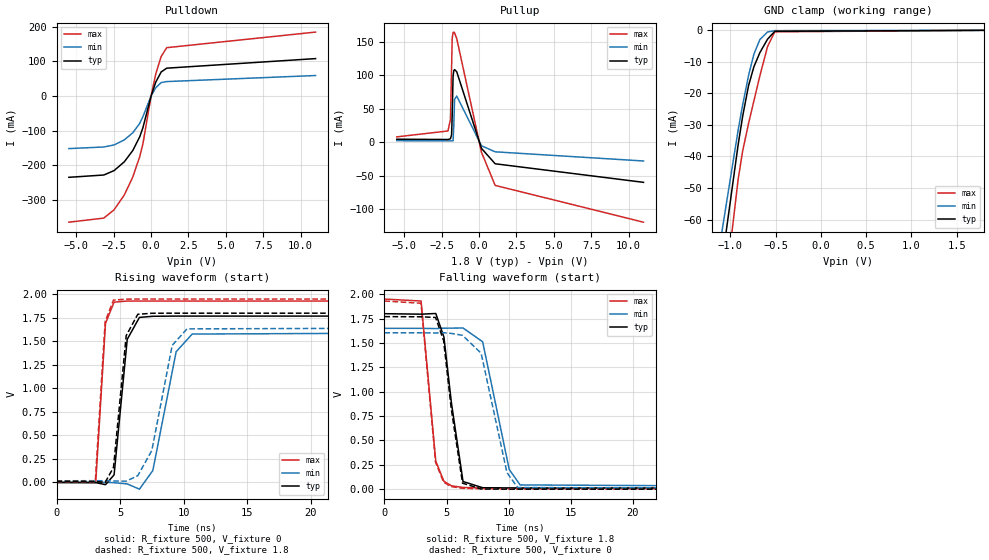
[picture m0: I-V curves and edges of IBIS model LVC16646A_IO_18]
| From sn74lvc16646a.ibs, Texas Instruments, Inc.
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[Model]   LVC16646A_IO_18
Model_type  I/O
Vinl=0.5775
Vinh=1.2675
Enable   Active-Low
Vref =   0
Rref =   1000
Cref =   30p
Vmeas =   0.9
| variable   typ   min   max
C_comp   8.38pF   7.45pF   9.23pF
| C_pullup   11.64pF   7.97pF   13.67pF
| C_pulldown   18.07pF   9.92pF   27.45pF
| C_tri-state   8.38pF   7.45pF   9.23pF
[Temperature Range]   40   100   -40
| Ambient temperature   25   85   -40
[Voltage range]   1.8   1.65   1.95
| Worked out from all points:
|   slope of the pulldown table from 0 to 0.27 V, typ, clamps not added: 7.6 ohm
|   slope of the pullup table from 0 to 0.27 V, typ, clamps not added: 18.9 ohm
|   GND clamp passes 1 mA (typ) near -0.54 V on its own axis
|   rising waveform, R_fixture 500, V_fixture 0: 20-80 % time 680ps typ, 1.28ns min, 406ps max; typ from 0 V to 1.77 V
|   falling waveform, R_fixture 500, V_fixture 1.8: 20-80 % time 837ps typ, 1.48ns min, 659ps max; typ from 1.8 V to 0.012 V
|   rising waveform, R_fixture 500, V_fixture 1.8: 20-80 % time 684ps typ, 1.34ns min, 405ps max; typ from 0.012 V to 1.8 V
|   falling waveform, R_fixture 500, V_fixture 0: 20-80 % time 828ps typ, 1.55ns min, 649ps max; typ from 1.77 V to 0 V
[GND Clamp]
| LVC16646A_IO_18
|   Voltage   I(typ)   I(min)   I(max)
-5.5V     -1.242A    -1.069A    -1.5A
-1.225V   -103.5mA   -89.45mA   -127.4mA
-1.15V    -86.25mA   -74.65mA   -106.5mA
-1.085V   -71.67mA   -62.15mA   -88.91mA
-915mV    -36.28mA   -31.65mA   -47.24mA
-865mV    -27.25mA   -23.61mA   -38.27mA
-800mV    -17.54mA   -14.3mA    -29.54mA
-740mV    -11.49mA   -7.496mA   -22.29mA
-675mV    -7.095mA   -2.938mA   -14.46mA
-590mV    -2.803mA   -517.9uA   -5.15mA
-510mV    -314.3uA   -105.1uA   -473.6uA
1.8V      74.45pA    10.28nA    30.94pA
[Pulldown]
| LVC16646A_IO_18
|   Voltage   I(typ)   I(min)   I(max)
-5.5V     -234.2mA   -151.4mA   -363.5mA
-3.16V    -227.5mA   -146.8mA   -351.7mA
-2.475V   -214.8mA   -140.9mA   -327.7mA
-1.795V   -189.6mA   -126.4mA   -285.3mA
-1.23V    -157.3mA   -106.1mA   -233.9mA
-760mV    -117.4mA   -78.76mA   -174.5mA
-545mV    -90.84mA   -58.98mA   -137mA
5mV       753.9uA    468.2uA    1.172mA
310mV     39.91mA    23.88mA    63.34mA
675mV     69.47mA    38.9mA     114.1mA
1.045V    80.31mA    41.7mA     139.4mA
11V       107.9mA    59.16mA    184.3mA
[Pullup]
| LVC16646A_IO_18
|   Voltage   I(typ)   I(min)   I(max)
-5.5V     4.549mA    2.354mA    8.057mA
-2.075V   4.074mA    2.072mA    16.88mA
-1.91V    5.207mA    2.05mA     34.32mA
-1.835V   11.22mA    2.037mA    111.3mA
-1.795V   39.25mA    2.03mA     155.2mA
-1.735V   98.9mA     2.253mA    164mA
-1.685V   107.2mA    27.08mA    164.7mA
-1.635V   108.7mA    64.12mA    163.5mA
-1.49V    105.3mA    69.03mA    155mA
165mV     -9.185mA   -5.242mA   -15.07mA
1.08V     -32.17mA   -14.31mA   -64.48mA
11V       -59.92mA   -28mA      -119.5mA
[Ramp]
| LVC16646A_IO_18
| variable   typ   min   max
dV/dt_r   1.10/7.07E-10   1.01/1.35E-09   1.17/4.16E-10
dV/dt_f   1.08/8.41E-10   0.98/1.48E-09   1.17/6.65E-10
R_load = 500
[Rising Waveform]
| LVC16646A_IO_18
R_fixture =   500
C_fixture =   0
L_fixture =   0
V_fixture =   0
V_fixture_min = 0
V_fixture_max = 0
|   Time   V(typ)   V(min)   V(max)
0s        342.7pV    2.139nV    223.3pV
3.085ns   -1.758mV   990.8uV    -792.7uV
3.855ns   -23.78mV   853.3uV    1.691V
4.53ns    80.73mV    -2.648mV   1.917V
5.565ns   1.522V     -15.41mV   1.929V
6.525ns   1.755V     -71.45mV   1.929V
7.58ns    1.767V     126.6mV    1.929V
9.415ns   1.769V     1.39V      1.929V
10.68ns   1.769V     1.578V     1.929V
50ns      1.769V     1.601V     1.929V
[Falling Waveform]
| LVC16646A_IO_18
R_fixture =   500
C_fixture =   0
L_fixture =   0
V_fixture =   1.8
V_fixture_min = 1.65
V_fixture_max = 1.95
|   Time   V(typ)   V(min)   V(max)
0s        1.8V       1.65V      1.95V
2.95ns    1.795V     1.65V      1.93V
4.135ns   1.802V     1.647V     288.3mV
4.79ns    1.561V     1.651V     80.39mV
5.395ns   884.8mV    1.652V     34.77mV
6.33ns    78.55mV    1.653V     17.18mV
7.91ns    14.77mV    1.512V     11.74mV
10.05ns   12.35mV    202.5mV    10.07mV
10.93ns   12.15mV    43.49mV    9.602mV
50ns      11.93mV    17.65mV    8.303mV
[Rising Waveform]
| LVC16646A_IO_18
R_fixture =   500
C_fixture =   0
L_fixture =   0
V_fixture =   1.8
V_fixture_min = 1.65
V_fixture_max = 1.95
|   Time   V(typ)   V(min)   V(max)
0s        11.9mV     17.57mV    8.295mV
3.05ns    10.83mV    18.47mV    8.207mV
3.83ns    697.7uV    18.08mV    1.713V
4.485ns   160.8mV    15.23mV    1.939V
5.485ns   1.562V     13.76mV    1.949V
6.395ns   1.788V     71.73mV    1.95V
7.5ns     1.799V     339.3mV    1.95V
9.105ns   1.8V       1.458V     1.95V
10.27ns   1.8V       1.633V     1.95V
50ns      1.8V       1.65V      1.95V
[Falling Waveform]
| LVC16646A_IO_18
R_fixture =   500
C_fixture =   0
L_fixture =   0
V_fixture =   0
V_fixture_min = 0
V_fixture_max = 0
|   Time   V(typ)   V(min)   V(max)
0s        1.77V      1.604V     1.93V
2.95ns    1.768V     1.604V     1.907V
4.12ns    1.761V     1.602V     273.9mV
4.765ns   1.525V     1.605V     72.09mV
5.375ns   831.2mV    1.598V     26.09mV
6.29ns    61.51mV    1.578V     8.865mV
7.79ns    1.936mV    1.394V     3.536mV
9.87ns    279.2uV    168.9mV    1.849mV
10.73ns   160uV      17.07mV    1.386mV
50ns      23.53uV    77.45uV    8.344uV
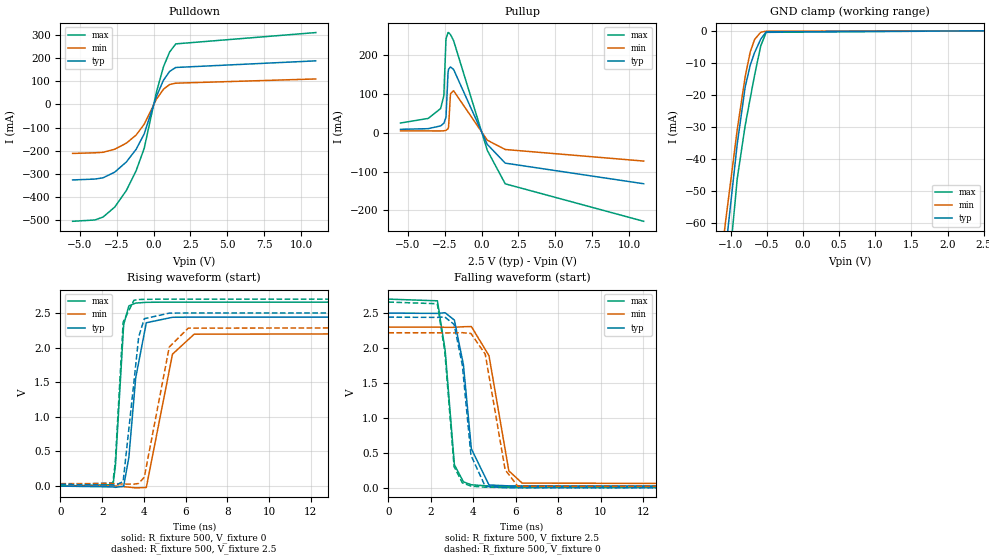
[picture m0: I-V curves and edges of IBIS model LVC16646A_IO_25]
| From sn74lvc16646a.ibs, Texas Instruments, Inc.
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[Model]   LVC16646A_IO_25
Model_type  I/O
Vinl=0.7
Vinh=1.7
Enable   Active-Low
Vref =   0
Rref =   500
Cref =   30p
Vmeas =   1.25
| variable   typ   min   max
C_comp   8.15pF   7.19pF   9.17pF
| C_pullup   11.44pF   7.76pF   13.11pF
| C_pulldown   17.46pF   9.78pF   26.07pF
| C_tri-state   8.15pF   7.19pF   9.17pF
[Temperature Range]   40   100   -40
| Ambient temperature   25   85   -40
[Voltage range]   2.5   2.3   2.7
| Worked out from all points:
|   slope of the pulldown table from 0 to 0.375 V, typ, clamps not added: 5.74 ohm
|   slope of the pullup table from 0 to 0.375 V, typ, clamps not added: 12.9 ohm
|   GND clamp passes 1 mA (typ) near -0.54 V on its own axis
|   rising waveform, R_fixture 500, V_fixture 0: 20-80 % time 434ps typ, 702ps min, 278ps max; typ from 0 V to 2.44 V
|   falling waveform, R_fixture 500, V_fixture 2.5: 20-80 % time 509ps typ, 723ps min, 414ps max; typ from 2.5 V to 0.025 V
|   rising waveform, R_fixture 500, V_fixture 2.5: 20-80 % time 429ps typ, 710ps min, 273ps max; typ from 0.025 V to 2.5 V
|   falling waveform, R_fixture 500, V_fixture 0: 20-80 % time 493ps typ, 699ps min, 404ps max; typ from 2.44 V to 0 V
[GND Clamp]
| LVC16646A_IO_25
|   Voltage   I(typ)   I(min)   I(max)
-5.5V     -1.242A    -1.069A    -1.5A
-1.22V    -102.3mA   -88.45mA   -126mA
-1.18V    -93.1mA    -80.52mA   -114.8mA
-1.145V   -85.11mA   -73.67mA   -105.2mA
-1.075V   -69.47mA   -60.26mA   -86.25mA
-910mV    -35.33mA   -30.82mA   -46.23mA
-800mV    -17.54mA   -14.3mA    -29.54mA
-730mV    -10.72mA   -6.593mA   -21.09mA
-670mV    -6.804mA   -2.707mA   -13.85mA
-585mV    -2.596mA   -451.1uA   -4.722mA
-510mV    -314.3uA   -105.1uA   -473.6uA
2.5V      103.2pA    21.14nA    42.76pA
[Pulldown]
| LVC16646A_IO_25
|   Voltage   I(typ)   I(min)   I(max)
-5.5V     -325.8mA   -211.4mA   -504.2mA
-3.99V    -322mA     -208.7mA   -498.5mA
-3.43V    -316.5mA   -206.4mA   -485.8mA
-2.64V    -292mA     -193.3mA   -442.7mA
-1.855V   -248.4mA   -167.1mA   -371.6mA
-1.19V    -193.8mA   -132.1mA   -286.2mA
-640mV    -126.9mA   -85.43mA   -188.9mA
180mV     33.53mA    21.64mA    51.16mA
665mV     104.3mA    65.37mA    162.1mA
1.08V     142.2mA    85.98mA    225.8mA
1.5V      159.4mA    91.64mA    261.2mA
11V       188mA      109.9mA    310mA
[Pullup]
| LVC16646A_IO_25
|   Voltage   I(typ)   I(min)   I(max)
-5.5V     9.01mA     5.077mA    25.29mA
-3.625V   10.65mA    4.878mA    37.09mA
-2.78V    17.79mA    4.79mA     62.41mA
-2.56V    24.7mA     5.188mA    95.82mA
-2.415V   39.59mA    6.341mA    242.3mA
-2.275V   155.3mA    10.48mA    258.6mA
-2.24V    164.2mA    14.97mA    258.4mA
-2.11V    169.8mA    100.8mA    253.4mA
-1.9V     163.5mA    108.5mA    237.9mA
390mV     -29.96mA   -19.1mA    -45.41mA
1.605V    -78.21mA   -43.06mA   -131.6mA
11V       -131.4mA   -72.93mA   -228.3mA
[Ramp]
| LVC16646A_IO_25
| variable   typ   min   max
dV/dt_r   1.48/4.44E-10   1.36/7.23E-10   1.61/2.89E-10
dV/dt_f   1.49/5.15E-10   1.36/7.30E-10   1.61/4.21E-10
R_load = 500
[Rising Waveform]
| LVC16646A_IO_25
R_fixture =   500
C_fixture =   0
L_fixture =   0
V_fixture =   0
V_fixture_min = 0
V_fixture_max = 0
|   Time   V(typ)   V(min)   V(max)
0s        362.9pV    1.698nV    247.1pV
2.52ns    -11.2mV    2.107mV    20.95mV
2.635ns   -17.58mV   1.984mV    296.9mV
3.03ns    -1.538mV   -7.938mV   2.332V
3.28ns    418mV      -15.08mV   2.603V
3.605ns   1.559V     -25.16mV   2.643V
4.115ns   2.359V     -20.51mV   2.654V
5.37ns    2.438V     1.905V     2.657V
6.41ns    2.44V      2.194V     2.657V
50ns      2.441V     2.216V     2.657V
[Falling Waveform]
| LVC16646A_IO_25
R_fixture =   500
C_fixture =   0
L_fixture =   0
V_fixture =   2.5
V_fixture_min = 2.3
V_fixture_max = 2.7
|   Time   V(typ)   V(min)   V(max)
0s        2.5V       2.3V       2.7V
2.31ns    2.496V     2.3V       2.676V
2.675ns   2.505V     2.297V     1.967V
3.11ns    2.4V       2.297V     331mV
3.535ns   1.762V     2.305V     85.63mV
3.91ns    558.3mV    2.308V     44.05mV
4.74ns    41.63mV    1.891V     26.42mV
5.675ns   28.26mV    243.5mV    22.7mV
6.3ns     26.62mV    68.28mV    21.77mV
50ns      25.28mV    35.74mV    18mV
[Rising Waveform]
| LVC16646A_IO_25
R_fixture =   500
C_fixture =   0
L_fixture =   0
V_fixture =   2.5
V_fixture_min = 2.3
V_fixture_max = 2.7
|   Time   V(typ)   V(min)   V(max)
0s        25.26mV    35.69mV    17.99mV
2.51ns    15.93mV    37.53mV    46.76mV
2.625ns   11.51mV    37.32mV    330mV
3.005ns   64.75mV    29.42mV    2.367V
3.525ns   1.512V     28.63mV    2.685V
3.75ns    2.155V     38.96mV    2.694V
4.02ns    2.417V     129.3mV    2.697V
5.215ns   2.498V     2.008V     2.7V
6.125ns   2.5V       2.281V     2.7V
50ns      2.5V       2.3V       2.7V
[Falling Waveform]
| LVC16646A_IO_25
R_fixture =   500
C_fixture =   0
L_fixture =   0
V_fixture =   0
V_fixture_min = 0
V_fixture_max = 0
|   Time   V(typ)   V(min)   V(max)
0s        2.442V     2.219V     2.658V
2.305ns   2.439V     2.219V     2.634V
2.655ns   2.445V     2.216V     1.96V
3.095ns   2.339V     2.217V     304.7mV
3.485ns   1.756V     2.22V      71.67mV
3.89ns    466.2mV    2.209V     24.83mV
4.565ns   19.37mV    1.912V     9.305mV
5.5ns     2.066mV    259.3mV    4.904mV
6.095ns   888uV      23.49mV    3.908mV
50ns      17.11uV    52.08uV    6.099uV
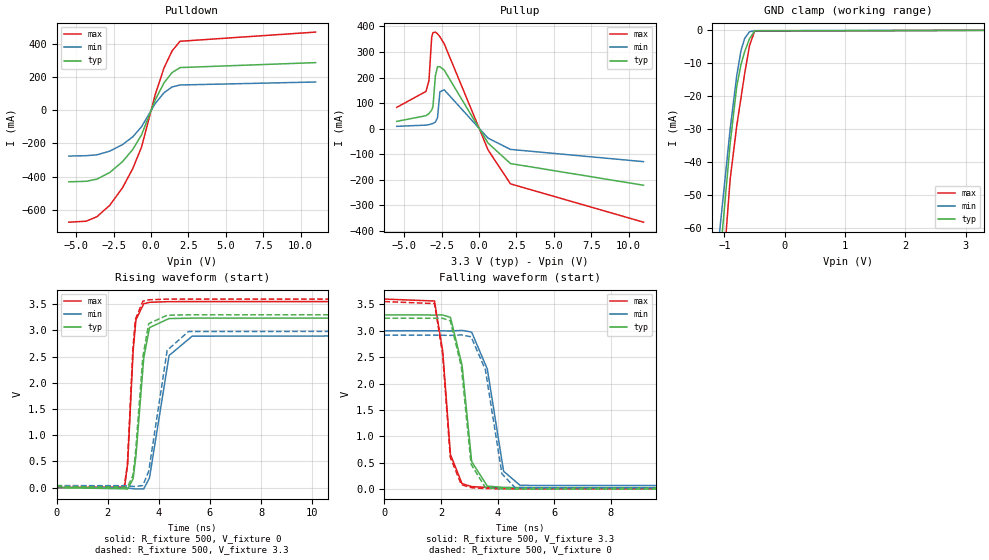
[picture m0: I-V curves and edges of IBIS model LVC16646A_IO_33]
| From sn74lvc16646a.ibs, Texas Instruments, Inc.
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[Model]   LVC16646A_IO_33
Model_type  I/O
Vinl=0.8
Vinh=2.0
Enable   Active-Low
Vref =   0
Rref =   500
Cref =   50p
Vmeas =   1.5
| variable   typ   min   max
C_comp   7.94pF   6.88pF   9.17pF
| C_pullup   11.22pF   7.53pF   13.14pF
| C_pulldown   16.83pF   9.68pF   24.46pF
| C_tri-state   7.94pF   6.88pF   9.17pF
[Temperature Range]   40   100   -40
| Ambient temperature   25   85   -40
[Voltage range]   3.3   3   3.6
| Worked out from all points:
|   slope of the pulldown table from 0 to 0.495 V, typ, clamps not added: 4.77 ohm
|   slope of the pullup table from 0 to 0.495 V, typ, clamps not added: 10.4 ohm
|   GND clamp passes 1 mA (typ) near -0.54 V on its own axis
|   rising waveform, R_fixture 500, V_fixture 0: 20-80 % time 324ps typ, 504ps min, 216ps max; typ from 0 V to 3.24 V
|   falling waveform, R_fixture 500, V_fixture 3.3: 20-80 % time 392ps typ, 517ps min, 318ps max; typ from 3.3 V to 0.028 V
|   rising waveform, R_fixture 500, V_fixture 3.3: 20-80 % time 317ps typ, 495ps min, 211ps max; typ from 0.028 V to 3.3 V
|   falling waveform, R_fixture 500, V_fixture 0: 20-80 % time 382ps typ, 500ps min, 313ps max; typ from 3.24 V to 0 V
[GND Clamp]
| LVC16646A_IO_33
|   Voltage   I(typ)   I(min)   I(max)
-5.5V     -1.242A    -1.069A    -1.5A
-1.23V    -104.7mA   -90.45mA   -128.8mA
-1.19V    -95.4mA    -82.49mA   -117.6mA
-1.15V    -86.25mA   -74.65mA   -106.5mA
-1.08V    -70.57mA   -61.21mA   -87.57mA
-905mV    -34.4mA    -29.99mA   -45.24mA
-795mV    -16.93mA   -13.65mA   -28.92mA
-725mV    -10.35mA   -6.169mA   -20.49mA
-665mV    -6.518mA   -2.49mA    -13.24mA
-585mV    -2.596mA   -451.1uA   -4.722mA
-500mV    -166.1uA   -94.34uA   -237.9uA
3.3V      141.6pA    30.12nA    55.2pA
[Pulldown]
| LVC16646A_IO_33
|   Voltage   I(typ)   I(min)   I(max)
-5.5V     -430.8mA   -276.2mA   -673.4mA
-4.34V    -427.7mA   -274mA     -667.5mA
-3.62V    -414.6mA   -268.7mA   -640.1mA
-2.765V   -374.9mA   -246.6mA   -571.9mA
-1.91V    -309.8mA   -207.1mA   -466.2mA
-1.22V    -235.9mA   -160mA     -350.4mA
-635mV    -147.9mA   -99.4mA    -220.8mA
280mV     61.98mA    40.34mA    94.37mA
865mV     164.1mA    104.4mA    253.8mA
1.4V      225.2mA    139mA      355mA
1.935V    255.4mA    150.8mA    413.4mA
11V       285.2mA    168.8mA    468.6mA
[Pullup]
| LVC16646A_IO_33
|   Voltage   I(typ)   I(min)   I(max)
-5.5V     28.45mA    8.944mA    83.37mA
-3.55V    50.65mA    13.75mA    145.6mA
-3.35V    58.77mA    15.68mA    187.3mA
-3.165V   72.54mA    18.44mA    357.8mA
-3.08V    86.36mA    20.27mA    375.8mA
-2.92V    206mA      25.78mA    377.9mA
-2.775V   242.3mA    42.42mA    371.3mA
-2.615V   242.3mA    144.1mA    359.7mA
-2.33V    229.3mA    152.1mA    332.5mA
605mV     -56.68mA   -37.34mA   -83.38mA
2.105V    -136.7mA   -81.32mA   -216.2mA
11V       -221.6mA   -129.2mA   -366.2mA
[Ramp]
| LVC16646A_IO_33
| variable   typ   min   max
dV/dt_r   1.96/3.33E-10   1.77/5.17E-10   2.15/2.27E-10
dV/dt_f   1.97/3.95E-10   1.78/5.27E-10   2.15/3.21E-10
R_load = 500
[Rising Waveform]
| LVC16646A_IO_33
R_fixture =   500
C_fixture =   0
L_fixture =   0
V_fixture =   0
V_fixture_min = 0
V_fixture_max = 0
|   Time   V(typ)   V(min)   V(max)
0s        400.2pV    1.536nV    280.5pV
2.66ns    -22.81mV   -2.092mV   11.78mV
2.78ns    -29.9mV    -8.857mV   448.4mV
2.995ns   169.4mV    -20.53mV   2.608V
3.105ns   606.9mV    -26.07mV   3.204V
3.41ns    2.475V     -24.31mV   3.511V
3.635ns   3.055V     186mV      3.538V
4.4ns     3.228V     2.522V     3.551V
5.305ns   3.236V     2.892V     3.552V
50ns      3.237V     2.915V     3.552V
[Falling Waveform]
| LVC16646A_IO_33
R_fixture =   500
C_fixture =   0
L_fixture =   0
V_fixture =   3.3
V_fixture_min = 3
V_fixture_max = 3.6
|   Time   V(typ)   V(min)   V(max)
0s        3.3V       3V         3.6V
1.77ns    3.298V     3V         3.563V
2.06ns    3.299V     2.998V     2.619V
2.335ns   3.254V     2.995V     654.5mV
2.745ns   2.346V     3.007V     104.9mV
3.085ns   522.2mV    2.974V     48.91mV
3.64ns    57.31mV    2.273V     31.19mV
4.215ns   33.66mV    338.8mV    26.82mV
4.8ns     29.95mV    71.84mV    25.12mV
50ns      27.84mV    38.53mV    20.07mV
[Rising Waveform]
| LVC16646A_IO_33
R_fixture =   500
C_fixture =   0
L_fixture =   0
V_fixture =   3.3
V_fixture_min = 3
V_fixture_max = 3.6
|   Time   V(typ)   V(min)   V(max)
0s        27.82mV    38.48mV    20.07mV
2.65ns    8.922mV    36.66mV    29.34mV
2.77ns    5.568mV    30.66mV    439.5mV
2.985ns   227mV      22.62mV    2.64V
3.08ns    621.9mV    20.89mV    3.208V
3.375ns   2.499V     41.08mV    3.559V
3.605ns   3.131V     315.9mV    3.586V
4.325ns   3.291V     2.62V      3.599V
5.155ns   3.299V     2.98V      3.6V
50ns      3.3V       3V         3.6V
[Falling Waveform]
| LVC16646A_IO_33
R_fixture =   500
C_fixture =   0
L_fixture =   0
V_fixture =   0
V_fixture_min = 0
V_fixture_max = 0
|   Time   V(typ)   V(min)   V(max)
0s        3.238V     2.917V     3.553V
1.77ns    3.236V     2.917V     3.514V
2.055ns   3.236V     2.915V     2.572V
2.33ns    3.19V      2.912V     601.5mV
2.72ns    2.32V      2.921V     86.65mV
3.065ns   472.4mV    2.886V     28.09mV
3.57ns    30.64mV    2.263V     11.41mV
4.155ns   4.352mV    291.4mV    6.761mV
4.62ns    1.782mV    29.62mV    5.298mV
50ns      15.94uV    47.42uV    5.069uV
